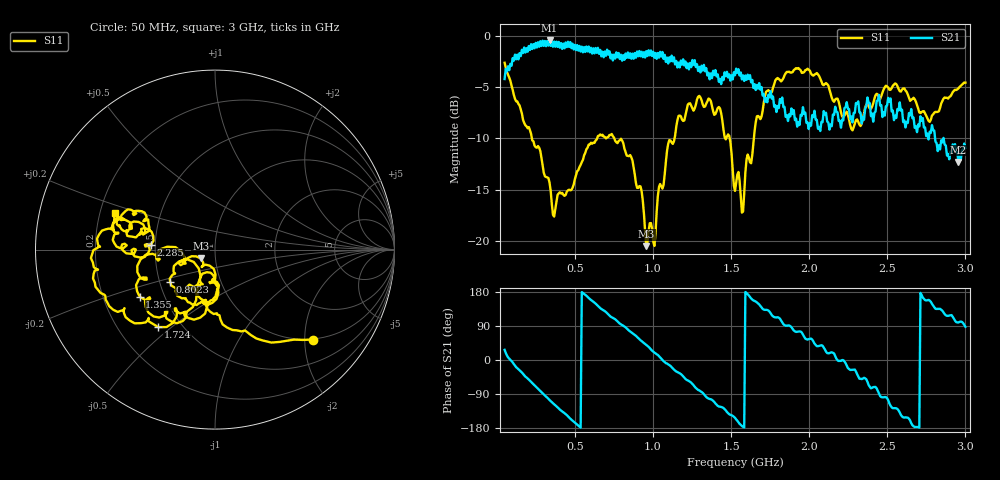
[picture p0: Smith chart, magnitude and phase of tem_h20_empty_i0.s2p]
! nanovna_capture.py 2026-10-26T21:46:57+0900
! NanoVNA-F_V2 fw 0.6.0 SN 4A3639384505514B
! cal: load open short thru cal'ed  over 50000000-3000000000 Hz, 201 points
! points 401, avg 4
! TEM cell h=20, empty, start of interleaved run (cables moved back from the slot line)
# HZ S RI R 50
! S12 and S22 are not measured (written as 0)
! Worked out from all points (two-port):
!   401 points, 50 MHz to 3 GHz, reference 50 ohm
!   highest |S21| = -0.42 dB at 337.6 MHz (marker M1); lowest = -12.3 dB at 2.956 GHz (marker M2)
!   |S21| within 3 dB of the highest: 65.34 MHz to 1.302 GHz (1.237 GHz wide, 181 % of centre); 1.305 GHz to 1.333 GHz (27.98 MHz wide, 2.12 % of centre) (the widest 2 of 8)
!   lowest |S11| = -20.5 dB at 957.1 MHz (marker M3), VSWR 1.21, Z = 42.4 - j4.22 ohm
!   |S11| at or under -10 dB: 224.7 MHz to 642.2 MHz (417.5 MHz wide, 96.3 % of centre); 752.5 MHz to 1.138 GHz (385.4 MHz wide, 40.8 % of centre); 1.491 GHz to 1.646 GHz (154.7 MHz wide, 9.86 % of centre) (the widest 3 of 5)
!   S12 and S22 are empty: the file has one direction only
!   S11 on the Smith chart (normalised r, x): 50 MHz: 0.98, -2.19; 802.2 MHz: 0.57, -0.23; 1.355 GHz: 0.36, -0.25; 1.724 GHz: 0.37, -0.45; 2.285 GHz: 0.47, +0.03; 3 GHz: 0.26, +0.17
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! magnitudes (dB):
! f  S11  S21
! 50 MHz  -2.6  -4.2
! 337.6 MHz  -14.3  -0.4
! 367.1 MHz  -17.6  -0.5
! 544.1 MHz  -12.3  -1.0
! 662.1 MHz  -9.6  -1.3
! 802.2 MHz  -10.2  -2.4
! 920.2 MHz  -14.7  -2.0
! 957.1 MHz  -20.5  -1.5
! 1.009 GHz  -20.5  -2.1
! 1.038 GHz  -14.7  -2.1
! 1.164 GHz  -7.8  -2.6
! 1.355 GHz  -6.1  -3.6
! 1.429 GHz  -7.1  -4.2
! 1.525 GHz  -15.1  -3.8
! 1.577 GHz  -17.1  -3.8
! 1.724 GHz  -5.4  -6.0
! 2.019 GHz  -3.8  -7.7
! 2.285 GHz  -8.9  -7.5
! 2.513 GHz  -5.2  -6.4
! 2.764 GHz  -8.3  -10.1
! 2.956 GHz  -5.1  -12.3
! 3 GHz  -4.5  -10.9
